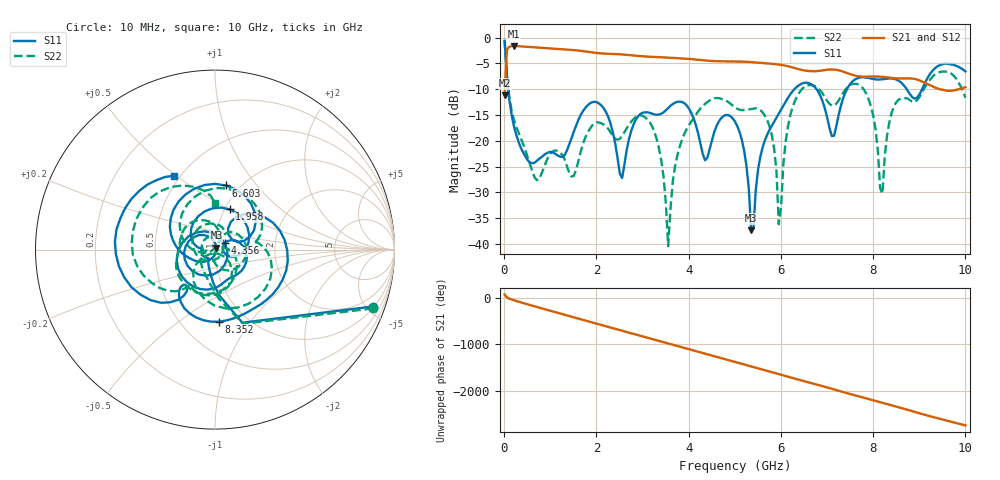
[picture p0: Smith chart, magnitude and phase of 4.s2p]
!Agilent Technologies,N5230C,MY49000813,A.09.42.22
!Agilent N5230C: A.09.42.22
!Date: Friday, August 21, 2026 19:35:25
!Correction: S11(Full 2 Port(1,2))
!S21(Full 2 Port(1,2))
!S12(Full 2 Port(1,2))
!S22(Full 2 Port(1,2))
!S2P File: Measurements: S11, S21, S12, S22:
# Hz S  dB  R 50
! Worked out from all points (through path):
!   201 points, 10 MHz to 10 GHz, reference 50 ohm
!   highest |S21| = -1.62 dB at 209.8 MHz (marker M1); lowest = -11.2 dB at 10 MHz (marker M2)
!   lowest |S11| = -37.4 dB at 5.355 GHz (marker M3), VSWR 1.03, Z = 50.8 + j1.11 ohm
!   |S11| at or under -10 dB: 89.72 MHz to 6.292 GHz (6.202 GHz wide, 194 % of centre); 6.772 GHz to 7.433 GHz (660.9 MHz wide, 9.3 % of centre); 8.727 GHz to 9.061 GHz (334.1 MHz wide, 3.76 % of centre)
!   |S22| runs from -40.4 to -0.5 dB; largest |S21 - S12| = 0.0056
!   S11 on the Smith chart (normalised r, x): 10 MHz: 1.11, -5.49; 1.958 GHz: 1.05, +0.50; 4.356 GHz: 1.11, +0.08; 6.603 GHz: 0.86, +0.71; 8.352 GHz: 0.75, -0.72; 10 GHz: 0.46, +0.49
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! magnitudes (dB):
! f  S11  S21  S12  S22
! 10 MHz  -0.6  -11.2  -11.3  -0.5
! 209.8 MHz  -17.1  -1.6  -1.6  -15.8
! 709.3 MHz  -23.9  -1.9  -1.9  -27.6
! 1.708 GHz  -14.3  -2.6  -2.6  -20.6
! 1.958 GHz  -12.4  -2.9  -2.9  -16.6
! 2.557 GHz  -27.2  -3.3  -3.3  -19.1
! 3.357 GHz  -14.9  -3.8  -3.8  -21.5
! 3.556 GHz  -13.7  -3.9  -3.9  -40.4
! 3.756 GHz  -12.4  -4.0  -4.0  -22.8
! 4.356 GHz  -23.8  -4.4  -4.4  -12.8
! 5.005 GHz  -16.3  -4.6  -4.6  -13.5
! 5.355 GHz  -37.4  -4.7  -4.7  -13.8
! 5.804 GHz  -17.1  -5.1  -5.1  -18.9
! 5.954 GHz  -14.7  -5.2  -5.2  -36.2
! 6.204 GHz  -11.0  -5.7  -5.7  -15.1
! 6.603 GHz  -8.8  -6.5  -6.5  -9.2
! 6.703 GHz  -9.3  -6.5  -6.5  -9.3
! 7.103 GHz  -19.1  -6.2  -6.2  -13.2
! 7.802 GHz  -7.7  -7.6  -7.6  -10.1
! 8.202 GHz  -8.1  -7.6  -7.6  -30.3
! 8.352 GHz  -7.9  -7.7  -7.8  -16.4
! 10 GHz  -6.5  -9.6  -9.6  -11.6
